VERSION 5.8 ;
BUSBITCHARS "[]" ;
DIVIDERCHAR "/" ;

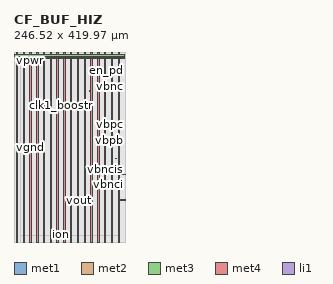
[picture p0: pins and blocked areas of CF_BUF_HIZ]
MACRO CF_BUF_HIZ
  CLASS BLOCK ;
  ORIGIN 0 0 ;
  FOREIGN CF_BUF_HIZ 0 0 ;
  SIZE 246.52 BY 419.97 ;
  PIN tp
    DIRECTION INPUT ;
    USE SIGNAL ;
    PORT
      LAYER met1 ;
        RECT 106.245 301.56 106.385 302.155 ;
    END
  END tp
  PIN vgnd
    DIRECTION INPUT ;
    USE GROUND ;
    PORT
      LAYER met1 ;
        RECT 231.225 376.455 231.515 376.985 ;
      LAYER met2 ;
        RECT 231.225 376.455 231.515 376.985 ;
      LAYER met3 ;
        RECT 231.205 376.455 231.79 376.985 ;
      LAYER met1 ;
        RECT 228.235 376.455 229.115 376.985 ;
      LAYER met2 ;
        RECT 228.235 376.455 229.115 376.985 ;
      LAYER met3 ;
        RECT 228.235 376.455 231.79 376.985 ;
        RECT 1.23 405.47 245.29 408.57 ;
      LAYER met4 ;
        RECT 20 0 23.1 419.97 ;
        RECT 50 0 53.1 419.97 ;
        RECT 80 0 83.1 419.97 ;
        RECT 110 0 113.1 419.97 ;
        RECT 140 0 143.1 419.97 ;
        RECT 170 0 173.1 419.97 ;
        RECT 200 0 203.1 419.97 ;
        RECT 230 0 233.1 419.97 ;
    END
  END vgnd
  PIN clk2_boost
    DIRECTION INPUT ;
    USE SIGNAL ;
    PORT
      LAYER met1 ;
        RECT 104.445 301.56 104.785 302.155 ;
    END
  END clk2_boost
  PIN clk1_boostr
    DIRECTION INPUT ;
    USE SIGNAL ;
    PORT
      LAYER met1 ;
        RECT 105.01 301.56 105.15 302.155 ;
    END
  END clk1_boostr
  PIN vbpt
    DIRECTION INPUT ;
    USE SIGNAL ;
    PORT
      LAYER met2 ;
        RECT 228.935 148.335 246.52 148.475 ;
    END
  END vbpt
  PIN vbpcis
    DIRECTION INOUT ;
    USE SIGNAL ;
    PORT
      LAYER met2 ;
        RECT 224.955 183.825 225.625 184.215 ;
    END
  END vbpcis
  PIN vbncis
    DIRECTION INOUT ;
    USE SIGNAL ;
    PORT
      LAYER met2 ;
        RECT 222.63 160.17 223.11 160.56 ;
    END
  END vbncis
  PIN vpwr
    DIRECTION INPUT ;
    USE POWER ;
    PORT
      LAYER met1 ;
        RECT 230.725 376.455 231.015 376.985 ;
      LAYER met2 ;
        RECT 230.725 375.675 231.015 376.985 ;
      LAYER met3 ;
        RECT 216.31 375.675 231.035 376.155 ;
      LAYER met1 ;
        RECT 229.6 376.455 230.48 376.985 ;
      LAYER met2 ;
        RECT 229.6 375.675 230.48 376.985 ;
      LAYER met3 ;
        RECT 216.31 375.675 230.48 376.155 ;
        RECT 1.23 410.27 245.29 413.37 ;
      LAYER met4 ;
        RECT 5 0 8.1 419.97 ;
        RECT 35 0 38.1 419.97 ;
        RECT 65 0 68.1 419.97 ;
        RECT 95 0 98.1 419.97 ;
        RECT 125 0 128.1 419.97 ;
        RECT 155 0 158.1 419.97 ;
        RECT 185 0 188.1 419.97 ;
        RECT 215 0 218.1 419.97 ;
    END
  END vpwr
  PIN vout
    DIRECTION OUTPUT ;
    USE SIGNAL ;
    PORT
      LAYER met2 ;
        RECT 142.875 90.545 143.605 90.98 ;
    END
  END vout
  PIN vbpci
    DIRECTION INPUT ;
    USE SIGNAL ;
    PORT
      LAYER met2 ;
        RECT 228.935 150.015 246.52 150.155 ;
    END
  END vbpci
  PIN vbnt
    DIRECTION INPUT ;
    USE SIGNAL ;
    PORT
      LAYER met2 ;
        RECT 226.135 129.44 226.525 129.83 ;
    END
  END vbnt
  PIN ibias
    DIRECTION INPUT ;
    USE SIGNAL ;
    PORT
      LAYER met2 ;
        RECT 167.59 333.55 168.075 333.94 ;
    END
  END ibias
  PIN ion
    DIRECTION INOUT ;
    USE SIGNAL ;
    PORT
      LAYER met1 ;
        RECT 104.89 14.91 105.06 15.4 ;
    END
  END ion
  PIN iop
    DIRECTION INOUT ;
    USE SIGNAL ;
    PORT
      LAYER met1 ;
        RECT 105.985 14.91 106.155 15.4 ;
    END
  END iop
  PIN e_pd
    DIRECTION INPUT ;
    USE SIGNAL ;
    PORT
      LAYER met1 ;
        RECT 226.075 379.46 226.415 380.015 ;
      LAYER li1 ;
        RECT 118.26 131.855 118.435 132.01 ;
    END
  END e_pd
  PIN vbnci
    DIRECTION INPUT ;
    USE SIGNAL ;
    PORT
      LAYER met2 ;
        RECT 226.135 127.765 226.525 128.155 ;
    END
  END vbnci
  PIN vbpcid
    DIRECTION INPUT ;
    USE SIGNAL ;
    PORT
      LAYER met2 ;
        RECT 230.61 92.515 246.52 92.655 ;
    END
  END vbpcid
  PIN vbptd
    DIRECTION INPUT ;
    USE SIGNAL ;
    PORT
      LAYER met2 ;
        RECT 230.61 93.365 246.52 93.505 ;
    END
  END vbptd
  PIN vbnc
    DIRECTION INOUT ;
    USE SIGNAL ;
    PORT
      LAYER met2 ;
        RECT 224.265 325.325 224.655 325.715 ;
    END
  END vbnc
  PIN vbpc
    DIRECTION INPUT ;
    USE SIGNAL ;
    PORT
      LAYER met2 ;
        RECT 225.635 277.97 226.025 278.36 ;
    END
  END vbpc
  PIN en_pd
    DIRECTION INPUT ;
    USE SIGNAL ;
    PORT
      LAYER met1 ;
        RECT 226.58 379.46 226.73 380.015 ;
    END
  END en_pd
  PIN vbpb
    DIRECTION INPUT ;
    USE SIGNAL ;
    PORT
      LAYER met2 ;
        RECT 217.16 224.505 217.565 224.895 ;
    END
  END vbpb
  PIN vinp_n
    DIRECTION INOUT ;
    USE SIGNAL ;
    PORT
      LAYER met1 ;
        RECT 102.775 300.345 102.92 300.92 ;
    END
  END vinp_n
  PIN vinn_n
    DIRECTION INOUT ;
    USE SIGNAL ;
    PORT
      LAYER met1 ;
        RECT 103.095 300.335 103.435 300.91 ;
    END
  END vinn_n
  PIN vinp_na
    DIRECTION INOUT ;
    USE SIGNAL ;
    PORT
      LAYER met1 ;
        RECT 102.415 300.345 102.56 300.92 ;
    END
  END vinp_na
  PIN vinn_na
    DIRECTION INOUT ;
    USE SIGNAL ;
    PORT
      LAYER met1 ;
        RECT 102.025 300.345 102.17 300.92 ;
    END
  END vinn_na
  PIN vinn_p
    DIRECTION INOUT ;
    USE SIGNAL ;
    PORT
      LAYER met1 ;
        RECT 101.285 299.635 101.43 300.21 ;
    END
  END vinn_p
  PIN vinp_p
    DIRECTION INOUT ;
    USE SIGNAL ;
    PORT
      LAYER met1 ;
        RECT 101.66 299.92 101.805 300.495 ;
    END
  END vinp_p
  PIN e_na_boost
    DIRECTION INPUT ;
    USE SIGNAL ;
    PORT
      LAYER met1 ;
        RECT 105.52 301.56 105.66 302.155 ;
    END
  END e_na_boost
  PIN e_n_boost
    DIRECTION INPUT ;
    USE SIGNAL ;
    PORT
      LAYER met1 ;
        RECT 105.875 301.56 106.015 302.155 ;
    END
  END e_n_boost
  OBS
    LAYER li1 ;
      RECT 0 0 246.52 419.97 ;
    LAYER met1 ;
      RECT 0 0 15 419.97 ;
      RECT 231.52 0 246.52 419.97 ;
      RECT 15 0 104.89 15 ;
      RECT 104.89 0 105.06 14.91 ;
      RECT 105.06 0 105.985 15 ;
      RECT 105.985 0 106.155 14.91 ;
      RECT 106.155 0 231.52 15 ;
      RECT 15 404.97 231.52 419.97 ;
    LAYER met2 ;
      RECT 0 0 15 419.97 ;
      RECT 231.52 0 246.52 92.515 ;
      RECT 231.52 92.655 246.52 93.365 ;
      RECT 231.52 93.505 246.52 148.335 ;
      RECT 231.52 148.475 246.52 150.015 ;
      RECT 231.52 150.155 246.52 419.97 ;
      RECT 15 0 231.52 15 ;
      RECT 15 404.97 231.52 419.97 ;
  END
END CF_BUF_HIZ

END LIBRARY
